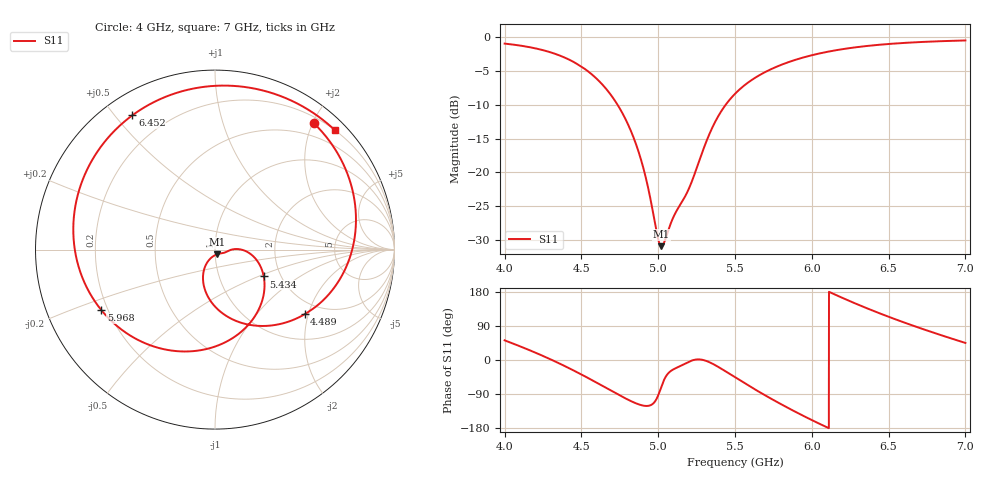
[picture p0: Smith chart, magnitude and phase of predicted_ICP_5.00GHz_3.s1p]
! ICP-predicted S11, target max centred GHz at -10 dB. Complex ensemble mean (passive and causal);
! its |S11| can differ slightly from the dB-domain mean reported in designs.csv.
!  Air_gap = 4.14mm
!  W_Patch = 17.1mm
!  L_Patch = 19.45mm
!  Sx = 0.66mm
!  Sy = 3.19mm
!  W_Patch1 = 12.47mm
!  WS = 0.83mm
!  Curve_Amp1 = 0.79mm
!  Extra = 4.93mm
# GHz S MA R 50
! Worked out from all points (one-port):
!   3001 points, 4 GHz to 7 GHz, reference 50 ohm
!   lowest |S11| = -30.9 dB at 5.021 GHz (marker M1), VSWR 1.06, Z = 50.9 - j2.73 ohm
!   |S11| at or under -10 dB: 4.735 GHz to 5.44 GHz (704.6 MHz wide, 13.9 % of centre)
!   S11 on the Smith chart (normalised r, x): 4 GHz: 0.29, +2.02; 4.489 GHz: 1.63, -1.89; 5.434 GHz: 1.63, -0.54; 5.968 GHz: 0.17, -0.24; 6.452 GHz: 0.08, +0.56; 7 GHz: 0.20, +2.40
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4  0.8936 51.9
4.111  0.8606 34.4
4.201  0.8238 19.3
4.289  0.7766 3.6
4.375  0.7173 -12.7
4.489  0.6155 -35.9
4.612  0.4763 -62.6
4.75  0.2964 -93.4
4.882  0.131 -118.2
4.932  0.07923 -121.1
4.997  0.03317 -96.0
5.021  0.02855 -69.9
5.125  0.05336 -19.5
5.204  0.07787 -3.8
5.309  0.1643 -1.9
5.434  0.3099 -28.8
5.5  0.3806 -45.6
5.592  0.467 -68.5
5.7  0.5535 -94.1
5.787  0.6139 -113.8
5.875  0.6678 -132.8
5.968  0.7176 -152.1
6.109  0.7802 -179.6
6.25  0.8288 154.9
6.452  0.8786 121.6
6.625  0.9073 95.5
6.799  0.9273 71.2
7  0.9426 45.0
